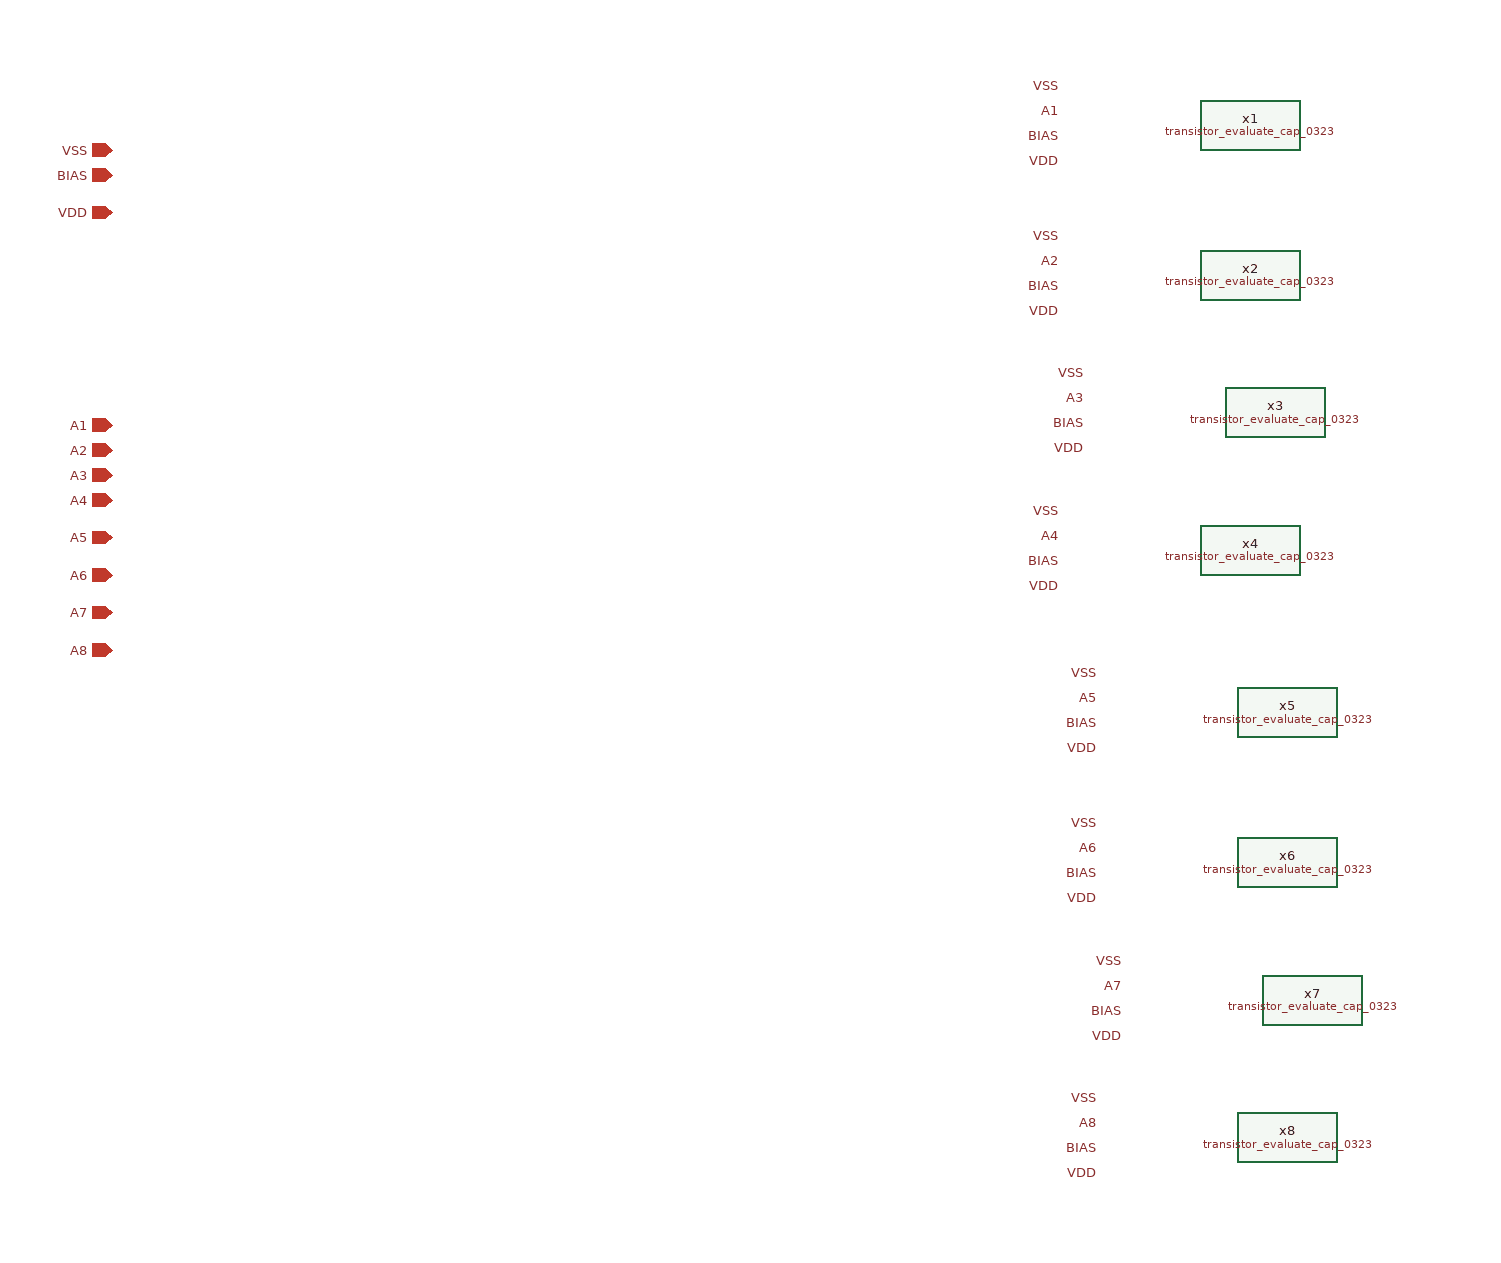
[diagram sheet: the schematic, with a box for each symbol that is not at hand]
v {xschem version=3.4.8RC file_version=1.3}
G {}
K {}
V {}
S {}
F {}
E {}
C {devices/ipin.sym} -1540 -690 0 0 {name=p1 lab=A2}
C {devices/ipin.sym} -1540 -670 0 0 {name=p2 lab=A3
}
C {devices/ipin.sym} -1540 -880 0 0 {name=p7 lab=VDD}
C {devices/ipin.sym} -1540 -710 0 0 {name=p3 lab=A1}
C {devices/ipin.sym} -1540 -930 0 0 {name=p11 lab=VSS}
C {devices/ipin.sym} -1540 -910 0 0 {name=p14 lab=BIAS
}
C {devices/lab_pin.sym} -780 -860 0 0 {name=p17 sig_type=std_logic lab=VSS}
C {devices/lab_pin.sym} -780 -820 0 0 {name=p26 sig_type=std_logic lab=BIAS}
C {devices/lab_pin.sym} -780 -840 0 0 {name=p34 sig_type=std_logic lab=A2}
C {devices/ipin.sym} -1540 -650 0 0 {name=p42 lab=A4}
C {devices/ipin.sym} -1540 -620 0 0 {name=p43 lab=A5
}
C {devices/ipin.sym} -1540 -590 0 0 {name=p44 lab=A6
}
C {devices/ipin.sym} -1540 -560 0 0 {name=p45 lab=A7
}
C {devices/ipin.sym} -1540 -530 0 0 {name=p46 lab=A8
}
C {devices/lab_pin.sym} -780 -800 0 0 {name=p4 sig_type=std_logic lab=VDD}
C {devices/lab_pin.sym} -760 -750 0 0 {name=p5 sig_type=std_logic lab=VSS}
C {devices/lab_pin.sym} -760 -710 0 0 {name=p6 sig_type=std_logic lab=BIAS}
C {devices/lab_pin.sym} -760 -730 0 0 {name=p8 sig_type=std_logic lab=A3}
C {devices/lab_pin.sym} -760 -690 0 0 {name=p9 sig_type=std_logic lab=VDD}
C {devices/lab_pin.sym} -780 -640 0 0 {name=p10 sig_type=std_logic lab=VSS}
C {devices/lab_pin.sym} -780 -600 0 0 {name=p12 sig_type=std_logic lab=BIAS}
C {devices/lab_pin.sym} -780 -620 0 0 {name=p13 sig_type=std_logic lab=A4}
C {devices/lab_pin.sym} -780 -580 0 0 {name=p15 sig_type=std_logic lab=VDD}
C {devices/lab_pin.sym} -780 -980 0 0 {name=p16 sig_type=std_logic lab=VSS}
C {devices/lab_pin.sym} -780 -940 0 0 {name=p18 sig_type=std_logic lab=BIAS}
C {devices/lab_pin.sym} -780 -960 0 0 {name=p19 sig_type=std_logic lab=A1}
C {devices/lab_pin.sym} -780 -920 0 0 {name=p20 sig_type=std_logic lab=VDD}
C {devices/lab_pin.sym} -750 -390 0 0 {name=p21 sig_type=std_logic lab=VSS}
C {devices/lab_pin.sym} -750 -350 0 0 {name=p22 sig_type=std_logic lab=BIAS}
C {devices/lab_pin.sym} -750 -370 0 0 {name=p23 sig_type=std_logic lab=A6}
C {devices/lab_pin.sym} -750 -330 0 0 {name=p24 sig_type=std_logic lab=VDD}
C {devices/lab_pin.sym} -730 -280 0 0 {name=p25 sig_type=std_logic lab=VSS}
C {devices/lab_pin.sym} -730 -240 0 0 {name=p27 sig_type=std_logic lab=BIAS}
C {devices/lab_pin.sym} -730 -260 0 0 {name=p28 sig_type=std_logic lab=A7}
C {devices/lab_pin.sym} -730 -220 0 0 {name=p29 sig_type=std_logic lab=VDD}
C {devices/lab_pin.sym} -750 -170 0 0 {name=p30 sig_type=std_logic lab=VSS}
C {devices/lab_pin.sym} -750 -130 0 0 {name=p31 sig_type=std_logic lab=BIAS}
C {devices/lab_pin.sym} -750 -150 0 0 {name=p32 sig_type=std_logic lab=A8}
C {devices/lab_pin.sym} -750 -110 0 0 {name=p33 sig_type=std_logic lab=VDD}
C {devices/lab_pin.sym} -750 -510 0 0 {name=p35 sig_type=std_logic lab=VSS}
C {devices/lab_pin.sym} -750 -470 0 0 {name=p36 sig_type=std_logic lab=BIAS}
C {devices/lab_pin.sym} -750 -490 0 0 {name=p37 sig_type=std_logic lab=A5}
C {devices/lab_pin.sym} -750 -450 0 0 {name=p38 sig_type=std_logic lab=VDD}
C {transistor_evaluate_cap_0323.sym} -630 -830 0 0 {name=x2}
C {transistor_evaluate_cap_0323.sym} -630 -950 0 0 {name=x1
}
C {transistor_evaluate_cap_0323.sym} -610 -720 0 0 {name=x3}
C {transistor_evaluate_cap_0323.sym} -630 -610 0 0 {name=x4}
C {transistor_evaluate_cap_0323.sym} -600 -480 0 0 {name=x5}
C {transistor_evaluate_cap_0323.sym} -600 -360 0 0 {name=x6}
C {transistor_evaluate_cap_0323.sym} -580 -250 0 0 {name=x7}
C {transistor_evaluate_cap_0323.sym} -600 -140 0 0 {name=x8}
